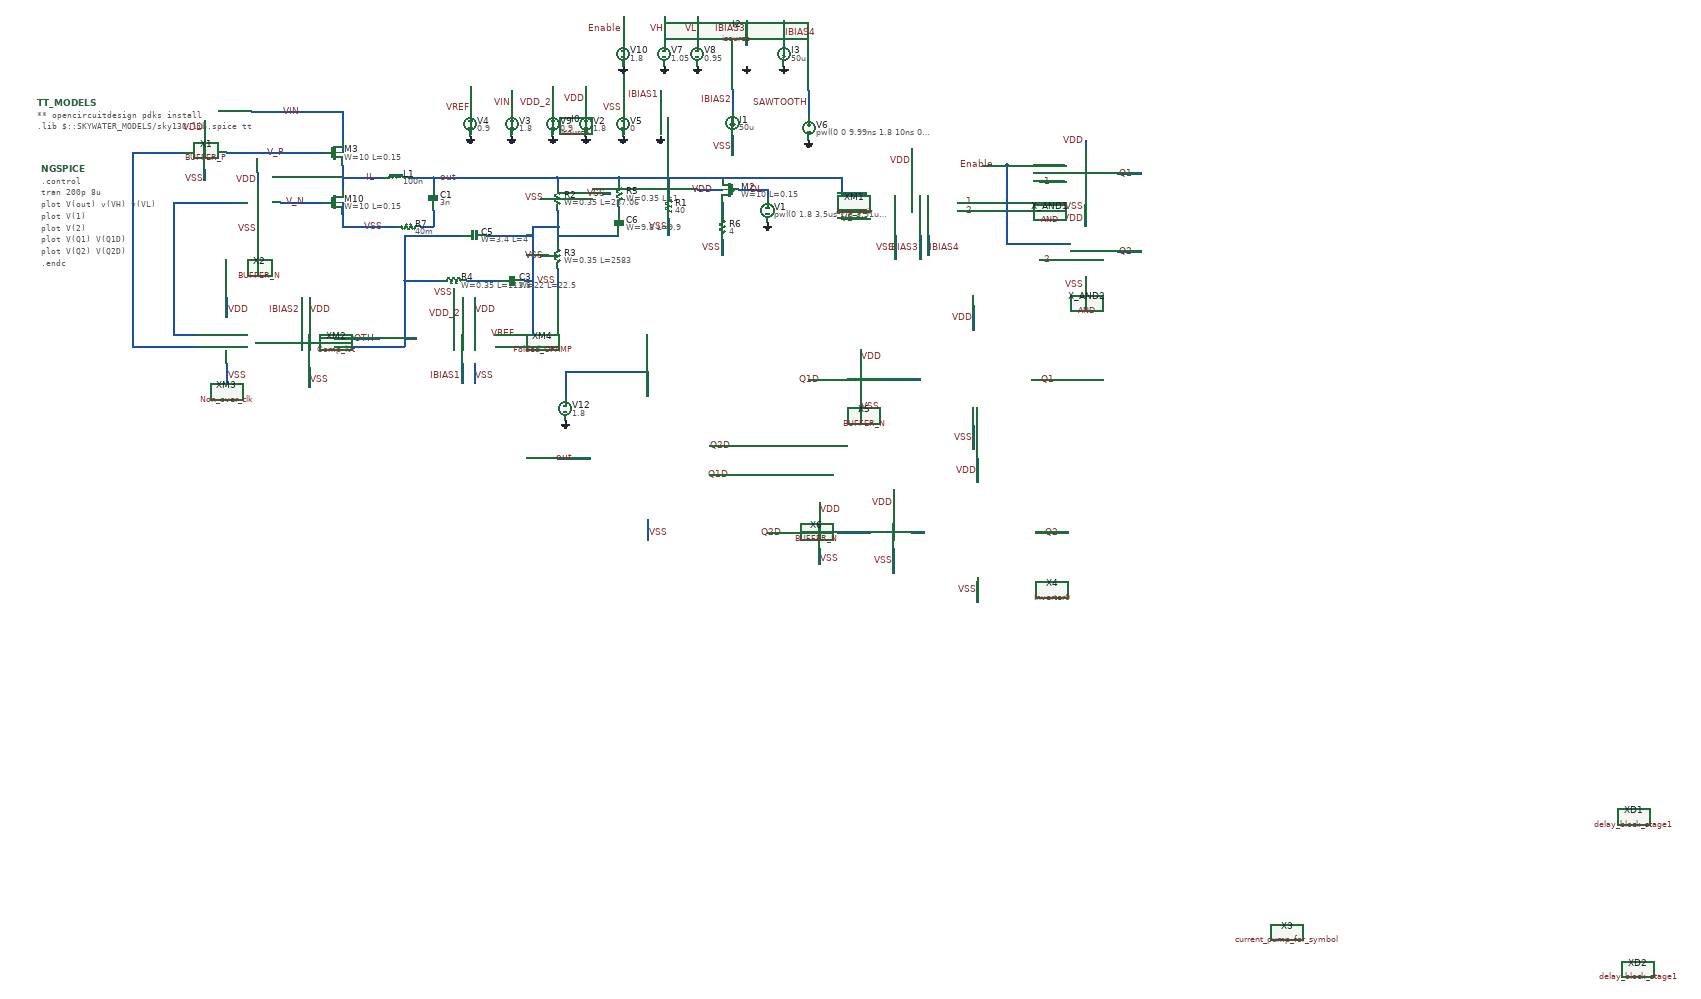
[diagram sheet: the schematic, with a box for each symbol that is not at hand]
v {xschem version=3.0.0 file_version=1.2 }
G {}
K {}
V {}
S {}
E {}
N 1920 940 1920 1000 {
lab=IL}
N 1920 880 1920 910 {
lab=VIN}
N 1830 910 1880 910 {
lab=V_P}
N 1920 810 1920 880 {
lab=VIN}
N 1700 810 1920 810 {
lab=VIN}
N 1920 1060 1920 1090 {
lab=VSS}
N 1920 970 1980 970 {
lab=IL}
N 1980 970 2020 970 {
lab=IL}
N 2140 970 2140 990 {
lab=out}
N 2080 970 2140 970 {
lab=out}
N 2140 1050 2140 1090 {
lab=#net1}
N 2140 970 2250 970 {
lab=out}
N 2240 1260 2240 1310 {
lab=VDD}
N 2210 1260 2210 1310 {
lab=VDD_2}
N 2240 1420 2240 1470 {
lab=VSS}
N 2210 1420 2210 1470 {
lab=IBIAS1}
N 2290 1380 2340 1380 {
lab=#net2}
N 2290 1350 2340 1350 {
lab=VREF}
N 2330 760 2330 810 {
lab=VIN}
N 2430 750 2430 810 {
lab=VDD_2}
N 2510 800 2510 810 {
lab=VDD}
N 2510 750 2510 800 {
lab=VDD}
N 2600 780 2600 800 {
lab=VSS}
N 2600 800 2600 810 {
lab=VSS}
N 2600 750 2600 780 {
lab=VSS}
N 2690 760 2690 820 {
lab=IBIAS1}
N 1840 1260 1840 1310 {
lab=VDD}
N 1840 1430 1840 1480 {
lab=VSS}
N 2230 780 2230 800 {
lab=VREF}
N 2230 800 2230 810 {
lab=VREF}
N 2230 750 2230 780 {
lab=VREF}
N 2340 1380 2370 1380 {
lab=#net2}
N 2865 867.5 2865 917.5 {
lab=VSS}
N 1820 1260 1820 1310 {
lab=IBIAS2}
N 3050 760 3050 820 {
lab=SAWTOOTH}
N 1640 910 1830 910 {
lab=V_P}
N 2250 970 2430 970 {
lab=out}
N 2440 970 2440 990 {
lab=out}
N 2440 1050 2440 1100 {
lab=#net2}
N 2440 1190 2440 1240 {
lab=VSS}
N 2220 1220 2300 1220 {
lab=#net3}
N 2070 1220 2160 1220 {
lab=#net4}
N 2070 1220 2070 1360 {
lab=#net4}
N 2380 1220 2380 1350 {
lab=#net2}
N 2360 1220 2380 1220 {
lab=#net2}
N 2070 1110 2210 1110 {
lab=#net4}
N 2270 1110 2380 1110 {
lab=#net2}
N 2380 1150 2380 1220 {
lab=#net2}
N 2070 1360 2100 1360 {
lab=#net4}
N 2380 1350 2380 1380 {
lab=#net2}
N 2370 1380 2380 1380 {
lab=#net2}
N 2440 970 2590 970 {
lab=out}
N 2590 970 2590 980 {
lab=out}
N 2590 1040 2590 1050 {
lab=#net5}
N 2430 970 2440 970 {
lab=out}
N 2380 1090 2380 1150 {
lab=#net2}
N 2380 1090 2440 1090 {
lab=#net2}
N 2440 1100 2440 1130 {
lab=#net2}
N 2710 970 2710 1010 {
lab=out}
N 2590 970 2710 970 {
lab=out}
N 2710 1070 2710 1110 {
lab=VSS}
N 1900 1380 2070 1380 {
lab=#net4}
N 2070 1360 2070 1380 {
lab=#net4}
N 1830 1030 1880 1030 {
lab=V_N}
N 1920 1030 1920 1060 {
lab=VSS}
N 2710 970 2840 970 {
lab=out}
N 2840 1120 2840 1160 {
lab=VSS}
N 2840 1030 2840 1060 {
lab=#net6}
N 2880 1000 2950 1000 {
lab=DL}
N 2950 1000 2950 1020 {
lab=DL}
N 1640 1260 1640 1310 {
lab=VDD}
N 1640 1420 1640 1470 {
lab=VSS}
N 1410 910 1540 910 {
lab=#net7}
N 1410 910 1410 1350 {
lab=#net7}
N 1585 950 1585 977.5 {
lab=VSS}
N 1585 832.5 1585 867.5 {
lab=VDD}
N 1770 1030 1830 1030 {
lab=V_N}
N 1510 1030 1670 1030 {
lab=#net8}
N 1510 1030 1510 1120 {
lab=#net8}
N 1715 1070 1715 1107.5 {
lab=VSS}
N 1715 957.5 1715 987.5 {
lab=VDD}
N 1510 1350 1570 1350 {
lab=#net8}
N 1510 1120 1510 1350 {
lab=#net8}
N 1410 1380 1570 1380 {
lab=#net7}
N 1410 1350 1410 1380 {
lab=#net7}
N 2070 1110 2070 1220 {
lab=#net4}
N 2440 1110 2490 1110 {
lab=#net2}
N 2490 1110 2590 1110 {
lab=#net2}
N 2240 1420 2240 1470 {
lab=VSS}
N 2780 1000 2840 1000 {
lab=VDD}
N 2865 757.5 2865 807.5 {
lab=IBIAS2}
N 1720 1370 1770 1370 {
lab=#net9}
N 1900 1360 2010 1360 {
lab=SAWTOOTH}
N 2190 1240 2190 1260 {
lab=VSS}
N 2550 1010 2570 1010 {
lab=VSS}
N 2400 1020 2420 1020 {
lab=VSS}
N 2400 1160 2420 1160 {
lab=VSS}
N 1920 1090 2050 1090 {
lab=VSS}
N 2110 1090 2140 1090 {
lab=#net1}
N 1710 1370 1720 1370 {
lab=#net9}
N 3410 1030 3460 1030 {
lab=1}
N 3410 1050 3460 1050 {
lab=2}
N 3340 1110 3340 1160 {
lab=IBIAS4}
N 3320 1110 3320 1170 {
lab=IBIAS3}
N 3260 1110 3260 1170 {
lab=VSS}
N 3300 900 3300 960 {
lab=VDD}
N 3130 1010 3190 1010 {
lab=out}
N 3130 1050 3190 1050 {
lab=VH}
N 3130 1070 3190 1070 {
lab=VL}
N 3130 970 3130 1010 {
lab=out}
N 2840 970 3130 970 {
lab=out}
N 2900 590 2900 650 {
lab=IBIAS3}
N 2990 590 2990 640 {
lab=IBIAS4}
N 3530 1130 3670 1130 {
lab=Enable}
N 3530 940 3670 940 {
lab=Enable}
N 3470 940 3530 940 {
lab=Enable}
N 3610 980 3670 980 {
lab=1}
N 3610 1170 3670 1170 {
lab=2}
N 3797.5 960 3857.5 960 {
lab=Q1}
N 3797.5 1150 3857.5 1150 {
lab=Q2}
N 3720 1210 3720 1230 {
lab=VSS}
N 3720 1070 3720 1090 {
lab=VDD}
N 3720 1020 3720 1040 {
lab=VSS}
N 3720 880 3720 900 {
lab=VDD}
N 3530 940 3530 1130 {
lab=Enable}
N 2700 580 2700 640 {
lab=VH}
N 2780 580 2780 640 {
lab=VL}
N 2600 580 2600 640 {
lab=Enable}
N 3450 1570 3450 1630 {
lab=VSS}
N 3450 1280 3450 1340 {
lab=VDD}
N 3590 1460 3670 1460 {
lab=Q1}
N 3220 1460 3320 1460 {
lab=#net10}
N 3460 1940 3460 2000 {
lab=VSS}
N 3460 1650 3460 1710 {
lab=VDD}
N 3600 1830 3680 1830 {
lab=Q2}
N 2660 1800 2660 1850 {
lab=VSS}
N 2660 1800 2660 1850 {
lab=VSS}
N 2440 1650 2520 1650 {
lab=out}
N 2810 1620 2880 1620 {
lab=Q2D}
N 2810 1690 2880 1690 {
lab=Q1D}
N 2460 1450 2460 1500 {
lab=#net11}
N 2660 1440 2660 1500 {
lab=#net11}
N 2460 1440 2660 1440 {
lab=#net11}
N 2460 1440 2460 1450 {
lab=#net11}
N 3120 1830 3200 1830 {
lab=#net12}
N 3255 1727.5 3255 1787.5 {
lab=VDD}
N 3255 1870 3255 1930 {
lab=VSS}
N 3300 1830 3330 1830 {
lab=#net13}
N 3050 1460 3120 1460 {
lab=Q1D}
N 3175 1500 3175 1537.5 {
lab=VSS}
N 3175 1387.5 3175 1417.5 {
lab=VDD}
N 2950 1830 3020 1830 {
lab=#net14}
N 3075 1870 3075 1907.5 {
lab=VSS}
N 3075 1757.5 3075 1787.5 {
lab=VDD}
C {sky130_fd_pr/pfet_01v8.sym} 1900 910 0 0 {name=M3
L=0.15
W=10
nf=1
mult=450
ad="'int((nf+1)/2) * W/nf * 0.29'" 
pd="'2*int((nf+1)/2) * (W/nf + 0.29)'"
as="'int((nf+2)/2) * W/nf * 0.29'" 
ps="'2*int((nf+2)/2) * (W/nf + 0.29)'"
nrd="'0.29 / W'" nrs="'0.29 / W'"
sa=0 sb=0 sd=0
model=pfet_01v8
spiceprefix=X
}
C {devices/ind.sym} 2050 970 3 0 {name=L1
m=1
value=100n
footprint=1206
device=inductor}
C {devices/capa.sym} 2140 1020 0 0 {name=C1
m=1
value=3n
footprint=1206
device="ceramic capacitor"}
C {devices/code.sym} 1180 790 0 0 {name=TT_MODELS
only_toplevel=true
format="tcleval( @value )"
value="
** opencircuitdesign pdks install
.lib $::SKYWATER_MODELS/sky130.lib.spice tt

"
spice_ignore=false}
C {devices/code_shown.sym} 1190 950 0 0 {name=NGSPICE
only_toplevel=true
value="

.control

tran 200p 8u
plot V(out) v(VH) v(VL)
plot V(1)
plot V(2) 
plot V(Q1) V(Q1D)
plot V(Q2) V(Q2D)
.endc
" }
C {devices/lab_wire.sym} 2200 970 0 0 {name=l4 sig_type=std_logic lab=out}
C {devices/lab_wire.sym} 2000 970 0 0 {name=l6 sig_type=std_logic lab=IL}
C {devices/lab_wire.sym} 1820 810 0 0 {name=l5 sig_type=std_logic lab=VIN}
C {devices/vsource.sym} 2330 840 0 0 {name=V3 value=1.8}
C {devices/gnd.sym} 2330 870 0 0 {name=l7 lab=GND}
C {devices/lab_wire.sym} 2330 790 0 0 {name=l2 sig_type=std_logic lab=VIN}
C {devices/gnd.sym} 2690 870 0 0 {name=l19 lab=GND}
C {devices/lab_wire.sym} 2690 770 0 0 {name=l22 sig_type=std_logic lab=IBIAS1}
C {devices/isource.sym} 2690 840 0 0 {name=I0 value=50u}
C {devices/vsource.sym} 2430 840 0 0 {name=V9 value=0.9}
C {devices/gnd.sym} 2430 870 0 0 {name=l42 lab=GND}
C {devices/lab_wire.sym} 2430 790 0 0 {name=l8 sig_type=std_logic lab=VDD_2}
C {devices/vsource.sym} 2510 840 0 0 {name=V2 value=1.8}
C {devices/gnd.sym} 2510 870 0 0 {name=l18 lab=GND}
C {devices/vsource.sym} 2600 840 0 0 {name=V5 value=0}
C {devices/gnd.sym} 2600 870 0 0 {name=l26 lab=GND}
C {devices/lab_wire.sym} 2600 800 0 0 {name=l10 sig_type=std_logic lab=VSS}
C {devices/lab_wire.sym} 2240 1290 0 1 {name=l13 sig_type=std_logic lab=VDD}
C {devices/lab_wire.sym} 2210 1300 0 0 {name=l14 sig_type=std_logic lab=VDD_2}
C {devices/lab_wire.sym} 2020 1090 0 0 {name=l1 sig_type=std_logic lab=VSS}
C {devices/lab_wire.sym} 2240 1450 0 1 {name=l15 sig_type=std_logic lab=VSS}
C {devices/lab_wire.sym} 2210 1450 0 0 {name=l16 sig_type=std_logic lab=IBIAS1}
C {devices/lab_wire.sym} 1840 1290 0 1 {name=l11 sig_type=std_logic lab=VDD}
C {devices/lab_wire.sym} 1840 1460 0 1 {name=l12 sig_type=std_logic lab=VSS}
C {devices/vsource.sym} 2230 840 0 0 {name=V4 value=0.9}
C {devices/gnd.sym} 2230 870 0 0 {name=l17 lab=GND}
C {devices/lab_wire.sym} 2230 800 0 0 {name=l20 sig_type=std_logic lab=VREF}
C {devices/isource.sym} 2865 837.5 0 1 {name=I1 value=50u}
C {devices/lab_wire.sym} 1820 1290 0 0 {name=l27 sig_type=std_logic lab=IBIAS2}
C {devices/vsource.sym} 3050 850 0 0 {name=V6 value="pwl(0 0 9.99ns 1.8 10ns 0) r=0"}
C {devices/gnd.sym} 3050 880 0 0 {name=l28 lab=GND}
C {devices/gnd.sym} 3050 880 0 0 {name=l29 lab=GND}
C {devices/lab_wire.sym} 3050 790 0 0 {name=l30 sig_type=std_logic lab=SAWTOOTH}
C {devices/lab_wire.sym} 2440 1220 0 0 {name=l31 sig_type=std_logic lab=VSS}
C {devices/lab_wire.sym} 2340 1350 0 0 {name=l33 sig_type=std_logic lab=VREF}
C {devices/lab_wire.sym} 2000 1360 0 0 {name=l32 sig_type=std_logic lab=SAWTOOTH}
C {devices/lab_wire.sym} 2710 1090 0 0 {name=l21 sig_type=std_logic lab=VSS}
C {sky130_fd_pr/pfet_01v8.sym} 2860 1000 0 1 {name=M2
L=0.15
W=10
nf=1
mult=450
ad="'int((nf+1)/2) * W/nf * 0.29'" 
pd="'2*int((nf+1)/2) * (W/nf + 0.29)'"
as="'int((nf+2)/2) * W/nf * 0.29'" 
ps="'2*int((nf+2)/2) * (W/nf + 0.29)'"
nrd="'0.29 / W'" nrs="'0.29 / W'"
sa=0 sb=0 sd=0
model=pfet_01v8
spiceprefix=X
}
C {devices/lab_wire.sym} 2840 1140 0 0 {name=l23 sig_type=std_logic lab=VSS}
C {devices/vsource.sym} 2950 1050 0 0 {name=V1 value="pwl(0 1.8 3.5us 1.8 3.51us 0 7us 0) r=0"}
C {devices/gnd.sym} 2950 1080 0 0 {name=l34 lab=GND}
C {devices/gnd.sym} 2950 1080 0 0 {name=l36 lab=GND}
C {devices/lab_wire.sym} 1640 1290 0 1 {name=l35 sig_type=std_logic lab=VDD}
C {devices/lab_wire.sym} 1640 1450 0 1 {name=l37 sig_type=std_logic lab=VSS}
C {DC_DC_Converter/BUFFER/BUFFER_PMOS/BUFFER_P.sym} 1520 960 0 0 {name=X1}
C {devices/lab_wire.sym} 1585 850 0 0 {name=l38 sig_type=std_logic lab=VDD}
C {devices/lab_wire.sym} 1585 972.5 0 0 {name=l40 sig_type=std_logic lab=VSS}
C {DC_DC_Converter/BUFFER/BUFFER_NMOS/BUFFER_N.sym} 1580 1110 0 0 {name=X2}
C {devices/lab_wire.sym} 1715 1095 0 0 {name=l39 sig_type=std_logic lab=VSS}
C {devices/lab_wire.sym} 1715 975 0 0 {name=l41 sig_type=std_logic lab=VDD}
C {DC_DC_Converter/Non_Overlap_Clk/Non_over_clk.sym} 1840 1630 0 1 {name=XM3}
C {devices/lab_wire.sym} 1780 910 0 0 {name=l3 sig_type=std_logic lab=V_P}
C {devices/lab_wire.sym} 1830 1030 0 0 {name=l43 sig_type=std_logic lab=V_N}
C {DC_DC_Converter/Folded_OPAMP/Folded_OPAMP.sym} 2300 1420 0 1 {name=XM4}
C {devices/lab_wire.sym} 2940 1000 0 0 {name=l96 sig_type=std_logic lab=DL}
C {sky130_fd_pr/cap_mim_m3_1.sym} 2240 1110 3 0 {name=C5 model=cap_mim_m3_1 W=3.4 L=4 MF=1 spiceprefix=X}
C {sky130_fd_pr/cap_mim_m3_1.sym} 2330 1220 3 0 {name=C3 model=cap_mim_m3_1 W=22 L=22.5 MF=1 spiceprefix=X}
C {sky130_fd_pr/cap_mim_m3_1.sym} 2590 1080 0 0 {name=C6 model=cap_mim_m3_1 W=9.8 L=9.9 MF=1 spiceprefix=X}
C {devices/lab_wire.sym} 2510 780 0 0 {name=l97 sig_type=std_logic lab=VDD}
C {devices/lab_wire.sym} 2820 1000 0 0 {name=l98 sig_type=std_logic lab=VDD}
C {sky130_fd_pr/nfet_01v8.sym} 1900 1030 0 0 {name=M10
L=0.15
W=10
nf=1 
mult=150
ad="'int((nf+1)/2) * W/nf * 0.29'" 
pd="'2*int((nf+1)/2) * (W/nf + 0.29)'"
as="'int((nf+2)/2) * W/nf * 0.29'" 
ps="'2*int((nf+2)/2) * (W/nf + 0.29)'"
nrd="'0.29 / W'" nrs="'0.29 / W'"
sa=0 sb=0 sd=0
model=nfet_01v8
spiceprefix=X
}
C {devices/lab_wire.sym} 2865 782.5 0 0 {name=l24 sig_type=std_logic lab=IBIAS2}
C {devices/lab_wire.sym} 2865 895 0 0 {name=l25 sig_type=std_logic lab=VSS}
C {sky130_fd_pr/res_high_po_0p35.sym} 2190 1220 3 0 {name=R4
W=0.35
L=113.8
model=res_high_po_0p35
spiceprefix=X
mult=1}
C {devices/lab_wire.sym} 2190 1250 3 0 {name=l9 sig_type=std_logic lab=VSS}
C {sky130_fd_pr/res_high_po_0p35.sym} 2590 1010 0 0 {name=R5
W=0.35
L=1
model=res_high_po_0p35
spiceprefix=X
mult=1}
C {devices/lab_wire.sym} 2560 1010 0 0 {name=l44 sig_type=std_logic lab=VSS}
C {sky130_fd_pr/res_high_po_0p35.sym} 2440 1020 0 0 {name=R2
W=0.35
L=287.06
model=res_high_po_0p35
spiceprefix=X
mult=1}
C {devices/lab_wire.sym} 2410 1020 0 0 {name=l45 sig_type=std_logic lab=VSS}
C {sky130_fd_pr/res_high_po_0p35.sym} 2440 1160 0 0 {name=R3
W=0.35
L=2583
model=res_high_po_0p35
spiceprefix=X
mult=1}
C {devices/lab_wire.sym} 2410 1160 0 0 {name=l46 sig_type=std_logic lab=VSS}
C {devices/res.sym} 2080 1090 1 0 {name=R7
value=40m
footprint=1206
device=resistor
m=1}
C {devices/res.sym} 2710 1040 0 0 {name=R1
value=40
footprint=1206
device=resistor
m=1}
C {devices/res.sym} 2840 1090 0 0 {name=R6
value=4
footprint=1206
device=resistor
m=1}
C {DC_DC_Converter/Comparator/Comp_lvt.sym} 1920 1440 0 1 {name=XM2}
C {devices/lab_wire.sym} 3340 1140 0 1 {name=l48 sig_type=std_logic lab=IBIAS4}
C {devices/lab_wire.sym} 3320 1140 0 0 {name=l49 sig_type=std_logic lab=IBIAS3}
C {devices/lab_pin.sym} 3260 1140 0 0 {name=l50 sig_type=std_logic lab=VSS}
C {devices/lab_pin.sym} 3300 930 0 0 {name=l51 sig_type=std_logic lab=VDD}
C {devices/lab_pin.sym} 3160 1050 1 0 {name=l53 sig_type=std_logic lab=VH}
C {devices/lab_pin.sym} 3160 1070 3 0 {name=l54 sig_type=std_logic lab=VL}
C {DC_DC_Converter/Comparator_Pair/cmp_pair.sym} 3170 1110 0 0 {name=XM1}
C {devices/lab_wire.sym} 3450 1030 0 0 {name=l47 sig_type=std_logic lab=1}
C {devices/lab_wire.sym} 3450 1050 0 0 {name=l87 sig_type=std_logic lab=2}
C {devices/gnd.sym} 2900 700 0 0 {name=l58 lab=GND}
C {devices/isource.sym} 2900 670 0 0 {name=I2 value=50u}
C {devices/isource.sym} 2990 670 0 0 {name=I3 value=50u}
C {devices/gnd.sym} 2990 700 0 0 {name=l60 lab=GND}
C {devices/lab_wire.sym} 2900 610 0 0 {name=l59 sig_type=std_logic lab=IBIAS3}
C {devices/lab_wire.sym} 2990 620 0 1 {name=l61 sig_type=std_logic lab=IBIAS4}
C {devices/lab_pin.sym} 3720 1230 0 0 {name=l84 sig_type=std_logic lab=VSS}
C {devices/lab_wire.sym} 3837.5 1150 0 0 {name=l86 sig_type=std_logic lab=Q2}
C {devices/lab_wire.sym} 3640 980 0 0 {name=l64 sig_type=std_logic lab=1}
C {devices/lab_wire.sym} 3640 1170 0 0 {name=l88 sig_type=std_logic lab=2}
C {devices/lab_wire.sym} 3500 940 0 0 {name=l91 sig_type=std_logic lab=Enable}
C {devices/lab_pin.sym} 3720 1070 0 0 {name=l94 sig_type=std_logic lab=VDD}
C {devices/lab_wire.sym} 3837.5 960 0 0 {name=l79 sig_type=std_logic lab=Q1}
C {devices/lab_pin.sym} 3720 1040 0 0 {name=l52 sig_type=std_logic lab=VSS}
C {devices/lab_pin.sym} 3720 880 0 0 {name=l55 sig_type=std_logic lab=VDD}
C {devices/vsource.sym} 2700 670 0 0 {name=V7 value=1.05}
C {devices/gnd.sym} 2700 700 0 0 {name=l56 lab=GND}
C {devices/lab_pin.sym} 2700 610 0 0 {name=l57 sig_type=std_logic lab=VH}
C {devices/vsource.sym} 2780 670 0 0 {name=V8 value=0.95}
C {devices/gnd.sym} 2780 700 0 0 {name=l65 lab=GND}
C {devices/lab_pin.sym} 2780 610 0 0 {name=l66 sig_type=std_logic lab=VL}
C {devices/gnd.sym} 2600 700 0 0 {name=l89 lab=GND}
C {devices/lab_pin.sym} 2600 610 0 0 {name=l90 sig_type=std_logic lab=Enable}
C {devices/vsource.sym} 2600 670 0 0 {name=V10 value=1.8}
C {DC_DC_Converter/Delay_block_revised/AND_GATE/AND.sym} 3650 1030 0 0 {name=X_AND1}
C {DC_DC_Converter/Delay_block_revised/AND_GATE/AND.sym} 3650 1220 0 0 {name=X_AND2}
C {devices/lab_pin.sym} 3450 1600 0 0 {name=l67 sig_type=std_logic lab=VSS}
C {devices/lab_pin.sym} 3450 1310 0 0 {name=l68 sig_type=std_logic lab=VDD}
C {devices/lab_wire.sym} 3647.5 1460 0 0 {name=l69 sig_type=std_logic lab=Q1}
C {devices/lab_pin.sym} 3460 1970 0 0 {name=l70 sig_type=std_logic lab=VSS}
C {devices/lab_pin.sym} 3460 1680 0 0 {name=l71 sig_type=std_logic lab=VDD}
C {devices/lab_wire.sym} 2987.5 1830 0 0 {name=l72 sig_type=std_logic lab=Q2D}
C {devices/lab_wire.sym} 3657.5 1830 0 0 {name=l73 sig_type=std_logic lab=Q2}
C {DC_DC_Converter/Delay_block_revised/delay_block_stage1.sym} 5050 2520 0 1 {name=XD1}
C {DC_DC_Converter/Delay_block_revised/delay_block_stage1.sym} 5060 2890 0 1 {name=XD2}
C {devices/lab_wire.sym} 2660 1830 0 1 {name=l103 sig_type=std_logic lab=VSS}
C {DC_DC_Converter/current_pump/current_pump_for_symbol.sym} 4210 2800 0 1 {name=X3}
C {devices/vsource.sym} 2460 1530 0 0 {name=V12 value=1.8}
C {devices/gnd.sym} 2460 1560 0 0 {name=l76 lab=GND}
C {devices/lab_wire.sym} 2857.5 1690 0 0 {name=l77 sig_type=std_logic lab=Q1D}
C {DC_DC_Converter/Delay_block_revised/Inverter_0/Inverter0.sym} 3520 1950 0 1 {name=X4}
C {devices/lab_pin.sym} 3255 1757.5 0 0 {name=l63 sig_type=std_logic lab=VDD}
C {devices/lab_pin.sym} 3255 1900 0 0 {name=l75 sig_type=std_logic lab=VSS}
C {devices/lab_wire.sym} 3080 1460 1 0 {name=l78 sig_type=std_logic lab=Q1D}
C {devices/lab_wire.sym} 2862.5 1620 0 0 {name=l74 sig_type=std_logic lab=Q2D}
C {devices/lab_wire.sym} 2480 1650 0 0 {name=l62 sig_type=std_logic lab=out}
C {DC_DC_Converter/BUFFER/BUFFER_NMOS/BUFFER_N.sym} 3310 1540 0 1 {name=X5}
C {devices/lab_wire.sym} 3175 1525 0 1 {name=l81 sig_type=std_logic lab=VSS}
C {devices/lab_wire.sym} 3175 1405 0 1 {name=l83 sig_type=std_logic lab=VDD}
C {DC_DC_Converter/BUFFER/BUFFER_NMOS/BUFFER_N.sym} 3210 1910 0 1 {name=X6}
C {devices/lab_wire.sym} 3075 1895 0 1 {name=l85 sig_type=std_logic lab=VSS}
C {devices/lab_wire.sym} 3075 1775 0 1 {name=l92 sig_type=std_logic lab=VDD}
